VERSION 5.7 ;
  NOWIREEXTENSIONATPIN ON ;
  DIVIDERCHAR "/" ;
  BUSBITCHARS "[]" ;
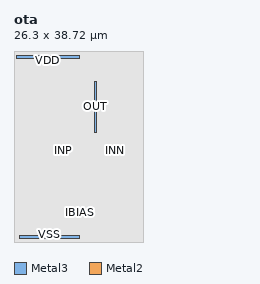
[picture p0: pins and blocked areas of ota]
MACRO ota
  CLASS BLOCK ;
  FOREIGN ota ;
  ORIGIN 13.260 3.940 ;
  SIZE 26.300 BY 38.720 ;
  PIN IBIAS
    ANTENNAGATEAREA 12.000000 ;
    ANTENNADIFFAREA 1.120000 ;
    PORT
      LAYER Metal3 ;
        RECT -0.600 2.020 1.160 2.300 ;
    END
  END IBIAS
  PIN OUT
    ANTENNADIFFAREA 1.792000 ;
    PORT
      LAYER Metal3 ;
        RECT 3.200 18.340 3.480 28.820 ;
    END
  END OUT
  PIN INN
    ANTENNAGATEAREA 4.000000 ;
    PORT
      LAYER Metal2 ;
        RECT 7.130 14.555 7.410 14.835 ;
    END
  END INN
  PIN INP
    ANTENNAGATEAREA 4.000000 ;
    PORT
      LAYER Metal2 ;
        RECT -3.410 14.555 -3.130 14.835 ;
    END
  END INP
  PIN VSS
    USE GROUND ;
    PORT
      LAYER Metal3 ;
        RECT -12.240 -3.220 0.140 -2.660 ;
    END
  END VSS
  PIN VDD
    USE POWER ;
    PORT
      LAYER Metal3 ;
        RECT -12.840 33.500 0.140 34.060 ;
    END
  END VDD
  OBS
      LAYER Nwell ;
        RECT -10.040 0.000 10.040 30.890 ;
      LAYER Metal1 ;
        RECT -9.810 0.210 9.810 30.680 ;
      LAYER Metal2 ;
        RECT -10.170 15.135 9.810 30.970 ;
        RECT -10.170 14.255 -3.710 15.135 ;
        RECT -2.830 14.255 6.830 15.135 ;
        RECT 7.710 14.255 9.810 15.135 ;
        RECT -10.170 0.210 9.810 14.255 ;
      LAYER Metal3 ;
        RECT -13.260 33.920 -12.840 34.060 ;
        RECT -13.260 33.640 -13.120 33.920 ;
        RECT -13.260 33.500 -12.840 33.640 ;
        RECT -13.260 33.200 -13.140 33.500 ;
        RECT 0.440 33.200 12.800 34.060 ;
        RECT -13.260 29.120 12.800 33.200 ;
        RECT -13.260 18.040 2.900 29.120 ;
        RECT 3.780 18.040 12.800 29.120 ;
        RECT -13.260 2.600 12.800 18.040 ;
        RECT -13.260 1.720 -0.900 2.600 ;
        RECT 1.460 1.720 12.800 2.600 ;
        RECT -13.260 -2.360 12.800 1.720 ;
        RECT -13.260 -3.220 -12.540 -2.360 ;
        RECT 0.440 -3.220 12.800 -2.360 ;
      LAYER Metal4 ;
        RECT -13.230 -3.190 12.770 34.030 ;
      LAYER Metal5 ;
        RECT -13.230 -3.940 13.040 34.780 ;
  END
END ota
END LIBRARY

